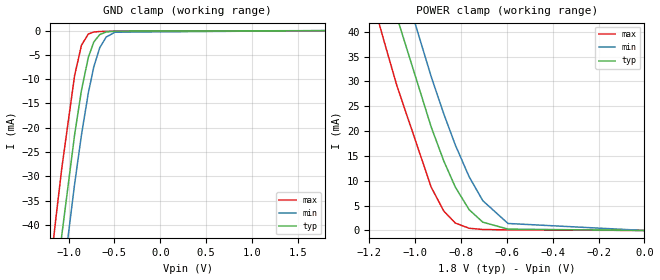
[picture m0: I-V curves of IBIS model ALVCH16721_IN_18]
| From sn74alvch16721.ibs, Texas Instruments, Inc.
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[Model]   ALVCH16721_IN_18
Model_type  Input
Vinl=0.5775
Vinh=1.2675
| variable   typ   min   max
C_comp   1.81pF   1.57pF   1.95pF
[Temperature Range]   40   100   -40
| Ambient temperature   25   85   -40
[Voltage range]   1.8   1.65   1.95
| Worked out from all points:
|   GND clamp passes 1 mA (typ) near -0.67 V on its own axis
|   POWER clamp passes 1 mA (typ) near -0.67 V on its own axis
[GND Clamp]
| ALVCH16721_IN_18
|   Voltage   I(typ)   I(min)   I(max)
-1.8V     -169.8mA   -179.9mA   -157.2mA
-1.22V    -66.13mA   -76.92mA   -52.27mA
-1.14V    -52.74mA   -63.56mA   -38.84mA
-1.075V   -42.24mA   -53mA      -28.43mA
-935mV    -21.5mA    -31.67mA   -9.285mA
-860mV    -12.3mA    -21.51mA   -3.024mA
-785mV    -5.512mA   -12.84mA   -696.8uA
-725mV    -2.333mA   -7.439mA   -282.9uA
-660mV    -799.8uA   -3.501mA   -180.6uA
-590mV    -270.9uA   -1.321mA   -147.3uA
-495mV    -104.2uA   -323.7uA   -120.3uA
1.8V      1.112nA    11.43uA    -24.52uA
[POWER Clamp]
| ALVCH16721_IN_18
|   Voltage   I(typ)   I(min)   I(max)
-1.8V     169.8mA    179.9mA    157.1mA
-1.235V   68.65mA    79.45mA    54.78mA
-1.155V   55.19mA    66.01mA    41.26mA
-1.135V   51.89mA    62.71mA    37.96mA
-1.08V    43mA       53.78mA    29.16mA
-930mV    20.81mA    30.94mA    8.701mA
-875mV    13.96mA    23.43mA    3.896mA
-825mV    8.748mA    17.22mA    1.494mA
-765mV    4.203mA    10.85mA    450.1uA
-705mV    1.671mA    5.993mA    198.8uA
-595mV    272.6uA    1.408mA    118.5uA
-16.28fV  1.112nA    59.61nA    5.224pA
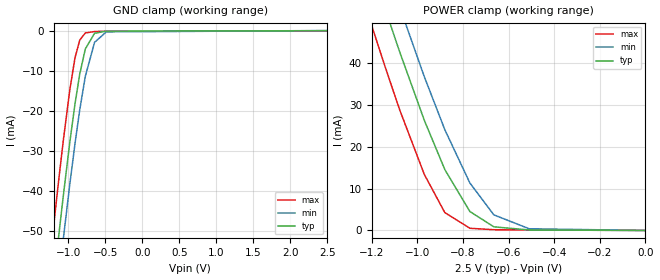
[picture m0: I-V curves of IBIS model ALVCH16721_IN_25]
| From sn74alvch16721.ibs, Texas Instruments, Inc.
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[Model]   ALVCH16721_IN_25
Model_type  Input
Vinl=0.7
Vinh=1.7
| variable   typ   min   max
C_comp   1.84pF   1.53pF   2.06pF
[Temperature Range]   40   100   -40
| Ambient temperature   25   85   -40
[Voltage range]   2.5   2.3   2.7
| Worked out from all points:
|   GND clamp passes 1 mA (typ) near -0.67 V on its own axis
|   POWER clamp passes 1 mA (typ) near -0.67 V on its own axis
[GND Clamp]
| ALVCH16721_IN_25
|   Voltage   I(typ)   I(min)   I(max)
-2.5V     -300.5mA   -309.8mA   -289mA
-1.22V    -66.17mA   -76.96mA   -52.33mA
-1.15V    -54.43mA   -65.24mA   -40.54mA
-1.125V   -50.32mA   -61.12mA   -36.44mA
-1.07V    -41.49mA   -52.23mA   -27.71mA
-980mV    -27.82mA   -38.28mA   -14.75mA
-910mV    -18.27mA   -28.18mA   -6.796mA
-845mV    -10.75mA   -19.66mA   -2.322mA
-770mV    -4.554mA   -11.37mA   -570.4uA
-645mV    -649.1uA   -2.895mA   -203.9uA
-485mV    -117.2uA   -296.6uA   -143.7uA
2.5V      1.114nA    24.46uA    -44.33uA
[POWER Clamp]
| ALVCH16721_IN_25
|   Voltage   I(typ)   I(min)   I(max)
-2.5V     300.4mA    309.8mA    288.9mA
-1.24V    69.54mA    80.33mA    55.69mA
-1.22V    66.13mA    76.94mA    52.26mA
-1.145V   53.57mA    64.39mA    39.65mA
-1.09V    44.63mA    55.42mA    30.77mA
-1.075V   42.25mA    53.01mA    28.42mA
-970mV    26.36mA    36.78mA    13.41mA
-880mV    14.57mA    24.11mA    4.278mA
-770mV    4.531mA    11.35mA    526.6uA
-665mV    874.9uA    3.74mA     180.5uA
-510mV    121uA      408.8uA    122.3uA
-31.15fV  1.114nA    59.61nA    7.128pA
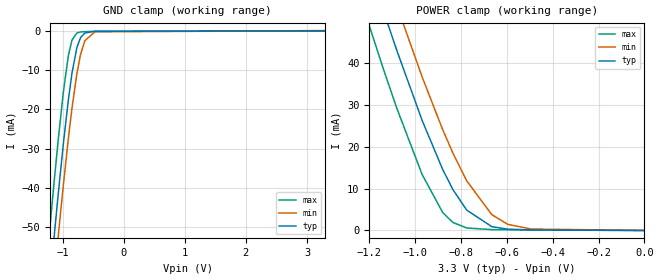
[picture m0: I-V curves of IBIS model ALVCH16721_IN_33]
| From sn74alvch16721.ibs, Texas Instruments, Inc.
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[Model]   ALVCH16721_IN_33
Model_type  Input
Vinl=0.8
Vinh=2.0
| variable   typ   min   max
C_comp   1.84pF   1.50pF   2.09pF
[Temperature Range]   40   100   -40
| Ambient temperature   25   85   -40
[Voltage range]   3.3   3   3.6
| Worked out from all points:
|   GND clamp passes 1 mA (typ) near -0.67 V on its own axis
|   POWER clamp passes 1 mA (typ) near -0.67 V on its own axis
[GND Clamp]
| ALVCH16721_IN_33
|   Voltage   I(typ)   I(min)   I(max)
-3.3V     -452.1mA   -460.8mA   -441.7mA
-1.225V   -67.05mA   -77.83mA   -53.23mA
-1.14V    -52.81mA   -63.61mA   -38.93mA
-1.07V    -41.52mA   -52.25mA   -27.75mA
-985mV    -28.58mA   -39.06mA   -15.45mA
-905mV    -17.66mA   -27.51mA   -6.374mA
-845mV    -10.77mA   -19.68mA   -2.354mA
-765mV    -4.276mA   -10.91mA   -557.3uA
-705mV    -1.739mA   -6.046mA   -298.4uA
-635mV    -574.4uA   -2.545mA   -223.6uA
-470mV    -123.2uA   -255uA     -158.8uA
3.3V      1.116nA    53.49uA    -78.26uA
[POWER Clamp]
| ALVCH16721_IN_33
|   Voltage   I(typ)   I(min)   I(max)
-3.3V     452.1mA    460.8mA    441.5mA
-1.23V    67.86mA    78.66mA    54.01mA
-1.14V    52.78mA    63.6mA     38.86mA
-1.08V    43.07mA    53.84mA    29.23mA
-970mV    26.39mA    36.8mA     13.44mA
-880mV    14.6mA     24.13mA    4.304mA
-835mV    9.751mA    18.46mA    1.894mA
-775mV    4.867mA    11.86mA    599.3uA
-665mV    894uA      3.758mA    201.9uA
-595mV    313uA      1.445mA    165.5uA
-495mV    124uA      344uA      135.2uA
-48.03fV  1.116nA    59.61nA    9.406pA
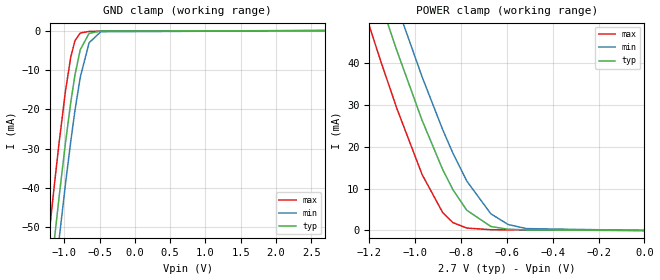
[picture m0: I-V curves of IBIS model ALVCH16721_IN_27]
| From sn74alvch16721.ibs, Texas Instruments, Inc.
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[Model]   ALVCH16721_IN_27
Model_type  Input
Vinl=0.8
Vinh=2.0
| variable   typ   min   max
C_comp   1.85pF   1.55pF   2.04pF
[Temperature Range]   40   100   -40
| Ambient temperature   25   85   -40
[Voltage range]   2.7   2.7   2.7
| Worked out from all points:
|   GND clamp passes 1 mA (typ) near -0.67 V on its own axis
|   POWER clamp passes 1 mA (typ) near -0.67 V on its own axis
[GND Clamp]
| ALVCH16721_IN_27
|   Voltage   I(typ)   I(min)   I(max)
-2.7V     -338.2mA   -347.4mA   -327.1mA
-1.24V    -69.58mA   -80.37mA   -55.76mA
-1.16V    -56.1mA    -66.91mA   -42.2mA
-1.135V   -51.97mA   -62.78mA   -38.07mA
-1.075V   -42.28mA   -53.04mA   -28.48mA
-985mV    -28.56mA   -39.05mA   -15.41mA
-910mV    -18.27mA   -28.19mA   -6.796mA
-850mV    -11.28mA   -20.29mA   -2.551mA
-775mV    -4.875mA   -11.87mA   -619.1uA
-650mV    -708.2uA   -3.102mA   -207.1uA
-485mV    -121.5uA   -303.9uA   -143.7uA
2.7V      1.115nA    59.61nA    7.128pA
[POWER Clamp]
| ALVCH16721_IN_27
|   Voltage   I(typ)   I(min)   I(max)
-2.7V     338.2mA    347.4mA    326.9mA
-1.23V    67.84mA    78.65mA    53.97mA
-1.15V    54.41mA    65.24mA    40.47mA
-1.08V    43.05mA    53.83mA    29.2mA
-970mV    26.37mA    36.79mA    13.41mA
-880mV    14.58mA    24.12mA    4.278mA
-835mV    9.734mA    18.45mA    1.869mA
-775mV    4.852mA    11.85mA    575.1uA
-670mV    956.3uA    3.994mA    184.7uA
-595mV    300.7uA    1.439mA    145.9uA
-515mV    130.2uA    448.2uA    123.5uA
-35.59fV  1.115nA    59.61nA    7.128pA
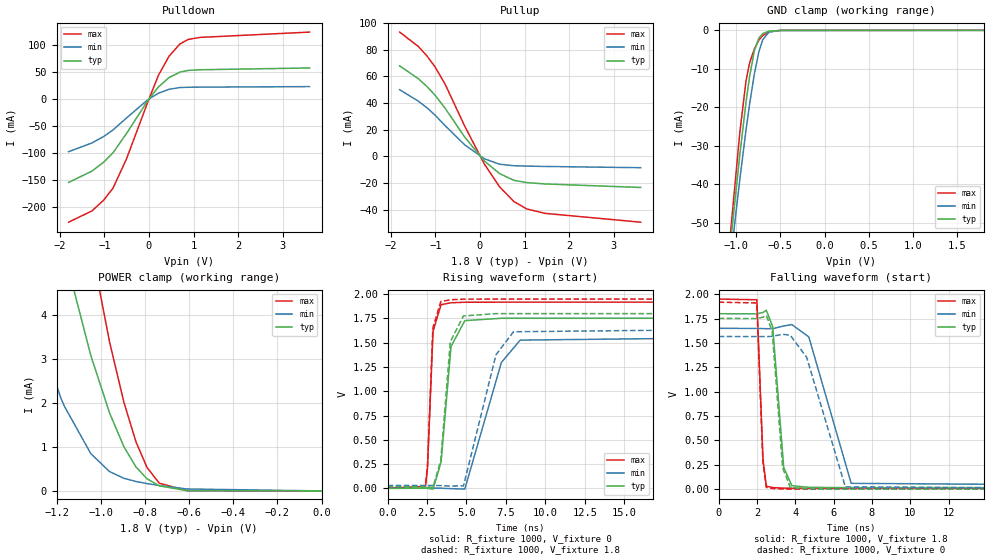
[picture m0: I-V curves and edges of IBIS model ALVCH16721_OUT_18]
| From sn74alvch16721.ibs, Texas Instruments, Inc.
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[Model]   ALVCH16721_OUT_18
Model_type  3-state
Enable   Active-Low
Vref =   0
Rref =   1000
Cref =   30p
Vmeas =   0.9
| variable   typ   min   max
C_comp   7.11pF   6.09pF   8.27pF
| C_pullup   8.07pF   7.48pF   8.71pF
| C_pulldown   9.93pF   7.67pF   11.83pF
| C_tri-state   7.11pF   6.09pF   8.27pF
[Temperature Range]   40   100   -40
| Ambient temperature   25   85   -40
[Voltage range]   1.8   1.65   1.95
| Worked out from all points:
|   slope of the pulldown table from 0 to 0.27 V, typ, clamps not added: 10 ohm
|   slope of the pullup table from 0 to 0.27 V, typ, clamps not added: 30.8 ohm
|   GND clamp passes 1 mA (typ) near -0.71 V on its own axis
|   POWER clamp passes 1 mA (typ) near -0.89 V on its own axis
|   rising waveform, R_fixture 1000, V_fixture 0: 20-80 % time 535ps typ, 1.34ns min, 273ps max; typ from 0 V to 1.75 V
|   falling waveform, R_fixture 1000, V_fixture 1.8: 20-80 % time 386ps typ, 961ps min, 182ps max; typ from 1.8 V to 0.015 V
|   rising waveform, R_fixture 1000, V_fixture 1.8: 20-80 % time 504ps typ, 1.14ns min, 264ps max; typ from 0.015 V to 1.8 V
|   falling waveform, R_fixture 1000, V_fixture 0: 20-80 % time 373ps typ, 973ps min, 182ps max; typ from 1.75 V to 0 V
[GND Clamp]
| ALVCH16721_OUT_18
|   Voltage   I(typ)   I(min)   I(max)
-1.8V     -243.3mA   -228.2mA   -268.4mA
-1.095V   -62.11mA   -65.74mA   -60.44mA
-1.065V   -55.21mA   -59.52mA   -52.47mA
-960mV    -32.27mA   -38.65mA   -26.5mA
-890mV    -18.68mA   -25.89mA   -13.15mA
-850mV    -12.06mA   -19.23mA   -8.522mA
-795mV    -5.259mA   -11.23mA   -4.781mA
-745mV    -2.029mA   -5.614mA   -2.577mA
-700mV    -849.2uA   -2.395mA   -1.322mA
-630mV    -224.4uA   -456.1uA   -398.2uA
-505mV    -19.57uA   -22.32uA   -41.45uA
1.8V      1.196nA    205.5pA    11.39nA
[POWER Clamp]
| ALVCH16721_OUT_18
|   Voltage   I(typ)   I(min)   I(max)
-1.8V     25.11mA    14.18mA    39.93mA
-1.415V   11.83mA    5.639mA    19.65mA
-1.18V    5.742mA    2.103mA    9.959mA
-1.165V   5.414mA    1.93mA     9.427mA
-1.045V   3.081mA    847.9uA    5.599mA
-960mV    1.772mA    439.6uA    3.385mA
-895mV    1.004mA    286.9uA    2.013mA
-840mV    542.1uA    213.7uA    1.108mA
-790mV    274.5uA    166.5uA    530uA
-735mV    115uA      123.6uA    176.7uA
-610mV    7.212uA    44.47uA    5.785uA
-16.28fV  1.196nA    59.55pA    11.28nA
[Pulldown]
| ALVCH16721_OUT_18
|   Voltage   I(typ)   I(min)   I(max)
-1.8V     -154.3mA   -97.53mA   -227.7mA
-1.275V   -133.3mA   -81.3mA    -206.8mA
-1.01V    -116.6mA   -69.29mA   -186.7mA
-805mV    -99.61mA   -57.36mA   -164.8mA
-505mV    -64.22mA   -35.41mA   -111.3mA
-20mV     -2.398mA   -1.172mA   -4.654mA
210mV     21.85mA    10.32mA    43.05mA
450mV     39.36mA    17.78mA    78.77mA
695mV     49.56mA    20.99mA    101.6mA
880mV     52.63mA    21.52mA    109.8mA
1.15V     53.84mA    21.74mA    113.6mA
3.6V      57.13mA    22.68mA    123.4mA
[Pullup]
| ALVCH16721_OUT_18
|   Voltage   I(typ)   I(min)   I(max)
-1.8V     67.82mA    49.93mA    93.11mA
-1.38V    58.14mA    41.32mA    82.29mA
-1.19V    52.37mA    36.44mA    75.34mA
-1.01V    45.98mA    31mA       67.22mA
-780mV    36mA       22.96mA    54.02mA
-340mV    14.33mA    8.546mA    22.47mA
105mV     -3.708mA   -1.929mA   -6.218mA
440mV     -12.97mA   -5.934mA   -22.89mA
760mV     -17.99mA   -7.06mA    -33.91mA
1.05V     -19.72mA   -7.341mA   -39.49mA
1.46V     -20.73mA   -7.61mA    -42.78mA
3.6V      -23.36mA   -8.547mA   -49.39mA
[Ramp]
| ALVCH16721_OUT_18
| variable   typ   min   max
dV/dt_r   1.06/5.42E-10   0.95/1.35E-09   1.16/2.80E-10
dV/dt_f   1.10/4.03E-10   1.00/9.99E-10   1.18/1.87E-10
R_load = 1000
[Rising Waveform]
| ALVCH16721_OUT_18
R_fixture =   1000
C_fixture =   0
L_fixture =   0
V_fixture =   0
V_fixture_min = 0
V_fixture_max = 0
|   Time   V(typ)   V(min)   V(max)
0s        299.4pV    583.6pV    166.6pV
2.405ns   902.4uV    855.7uV    19.84mV
2.53ns    756.5uV    1.082mV    210.1mV
2.88ns    -8.83mV    1.245mV    1.617V
3.39ns    269.6mV    1.194mV    1.892V
4.02ns    1.461V     -3.579mV   1.912V
4.895ns   1.728V     -7.83mV    1.917V
7.21ns    1.752V     1.296V     1.918V
8.4ns     1.752V     1.527V     1.918V
29.99ns   1.752V     1.566V     1.918V
[Falling Waveform]
| ALVCH16721_OUT_18
R_fixture =   1000
C_fixture =   0
L_fixture =   0
V_fixture =   1.8
V_fixture_min = 1.65
V_fixture_max = 1.95
|   Time   V(typ)   V(min)   V(max)
0s        1.8V       1.65V      1.95V
1.995ns   1.798V     1.649V     1.943V
2.315ns   1.812V     1.647V     304.7mV
2.49ns    1.835V     1.646V     30.75mV
2.82ns    1.667V     1.646V     16.49mV
3.395ns   223.6mV    1.674V     10.47mV
3.82ns    36.04mV    1.688V     9.234mV
4.705ns   18.35mV    1.562V     8.527mV
6.915ns   15.22mV    59.74mV    8.376mV
29.99ns   15.11mV    28.63mV    8.373mV
[Rising Waveform]
| ALVCH16721_OUT_18
R_fixture =   1000
C_fixture =   0
L_fixture =   0
V_fixture =   1.8
V_fixture_min = 1.65
V_fixture_max = 1.95
|   Time   V(typ)   V(min)   V(max)
0s        15.11mV    28.63mV    8.373mV
2.4ns     15.31mV    29.18mV    27.06mV
2.53ns    14.99mV    29.2mV     232.7mV
2.87ns    6.365mV    28.66mV    1.651V
3.37ns    286.1mV    27.64mV    1.924V
3.975ns   1.51V      23.18mV    1.943V
4.81ns    1.776V     24.93mV    1.949V
6.87ns    1.8V       1.376V     1.95V
7.98ns    1.8V       1.613V     1.95V
29.99ns   1.8V       1.65V      1.95V
[Falling Waveform]
| ALVCH16721_OUT_18
R_fixture =   1000
C_fixture =   0
L_fixture =   0
V_fixture =   0
V_fixture_min = 0
V_fixture_max = 0
|   Time   V(typ)   V(min)   V(max)
0s        1.752V     1.566V     1.918V
1.99ns    1.75V      1.565V     1.91V
2.31ns    1.764V     1.565V     280.2mV
2.49ns    1.782V     1.565V     16.93mV
2.795ns   1.62V      1.568V     7.697mV
3.34ns    220.6mV    1.589V     2.044mV
3.735ns   19.53mV    1.579V     876.8uV
4.59ns    2.691mV    1.354V     157.9uV
6.61ns    86.48uV    23.6mV     3.955uV
29.99ns   1.05nV     1.235nV    287.2pV
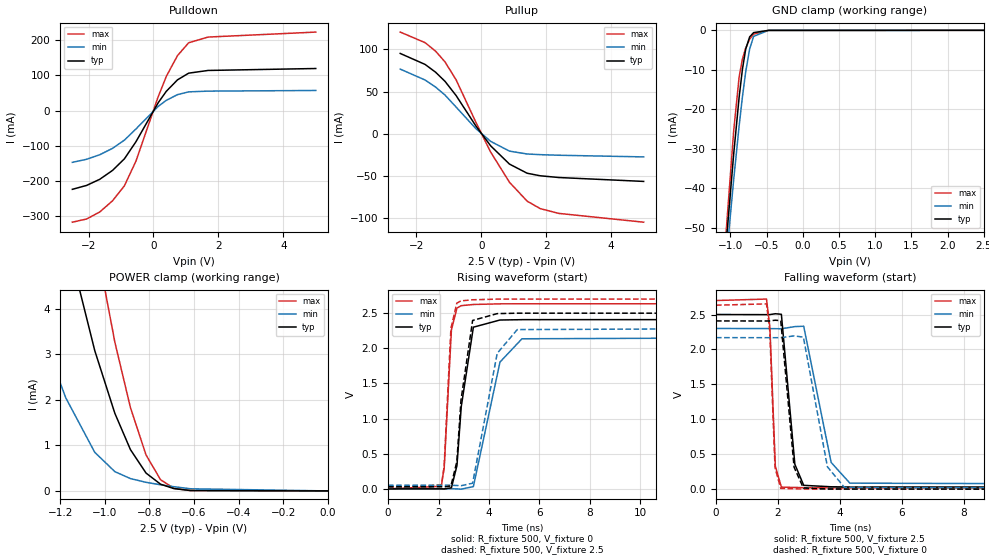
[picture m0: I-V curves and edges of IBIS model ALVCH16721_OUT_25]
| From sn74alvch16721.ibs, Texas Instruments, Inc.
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[Model]   ALVCH16721_OUT_25
Model_type  3-state
Enable   Active-Low
Vref =   0
Rref =   500
Cref =   30p
Vmeas =   1.25
| variable   typ   min   max
C_comp   6.82pF   5.80pF   8.17pF
| C_pullup   7.86pF   7.18pF   8.73pF
| C_pulldown   9.38pF   6.58pF   11.81pF
| C_tri-state   6.82pF   5.80pF   8.17pF
[Temperature Range]   40   100   -40
| Ambient temperature   25   85   -40
[Voltage range]   2.5   2.3   2.7
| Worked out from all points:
|   slope of the pulldown table from 0 to 0.375 V, typ, clamps not added: 7.11 ohm
|   slope of the pullup table from 0 to 0.375 V, typ, clamps not added: 20.7 ohm
|   GND clamp passes 1 mA (typ) near -0.71 V on its own axis
|   POWER clamp passes 1 mA (typ) near -0.89 V on its own axis
|   rising waveform, R_fixture 500, V_fixture 0: 20-80 % time 323ps typ, 588ps min, 209ps max; typ from 0 V to 2.41 V
|   falling waveform, R_fixture 500, V_fixture 2.5: 20-80 % time 228ps typ, 475ps min, 128ps max; typ from 2.5 V to 0.03 V
|   rising waveform, R_fixture 500, V_fixture 2.5: 20-80 % time 308ps typ, 527ps min, 205ps max; typ from 0.03 V to 2.5 V
|   falling waveform, R_fixture 500, V_fixture 0: 20-80 % time 219ps typ, 437ps min, 124ps max; typ from 2.41 V to 0 V
[GND Clamp]
| ALVCH16721_OUT_25
|   Voltage   I(typ)   I(min)   I(max)
-2.5V     -440.5mA   -405.4mA   -490.1mA
-1.09V    -60.95mA   -64.7mA    -59.1mA
-1.07V    -56.36mA   -60.55mA   -53.78mA
-1.055V   -52.94mA   -57.47mA   -49.85mA
-955mV    -31.24mA   -37.7mA    -25.39mA
-880mV    -16.92mA   -24.17mA   -11.77mA
-835mV    -9.895mA   -16.9mA    -7.298mA
-790mV    -4.809mA   -10.58mA   -4.52mA
-735mV    -1.667mA   -4.739mA   -2.241mA
-680mV    -581.8uA   -1.533mA   -953.6uA
-475mV    -10.99uA   -10.29uA   -24.43uA
2.5V      1.037nA    747.3pA    10.72nA
[POWER Clamp]
| ALVCH16721_OUT_25
|   Voltage   I(typ)   I(min)   I(max)
-2.5V     56.58mA    36.27mA    85.37mA
-1.405V   11.53mA    5.461mA    19.19mA
-1.28V    8.118mA    3.43mA     13.78mA
-1.175V   5.632mA    2.045mA    9.78mA
-1.045V   3.081mA    847.9uA    5.599mA
-955mV    1.705mA    423.9uA    3.269mA
-885mV    906.7uA    270.9uA    1.829mA
-815mV    391.2uA    188.7uA    788.2uA
-750mV    147.6uA    134.7uA    246.1uA
-690mV    50.51uA    92.37uA    57.6uA
-615mV    8.308uA    47.11uA    6.732uA
-31.15fV  1.037nA    68.08pA    10.48nA
[Pulldown]
| ALVCH16721_OUT_25
|   Voltage   I(typ)   I(min)   I(max)
-2.5V     -223.2mA   -146.6mA   -316.5mA
-2.06V    -212.1mA   -137.9mA   -307.4mA
-1.655V   -194.7mA   -125mA     -287.5mA
-1.26V    -169.4mA   -106.8mA   -255.7mA
-895mV    -136.5mA   -83.49mA   -213.1mA
-540mV    -88.14mA   -51.89mA   -143.3mA
145mV     22.52mA    12.19mA    39.65mA
395mV     55.03mA    29.41mA    97.31mA
740mV     87.57mA    45.62mA    156.4mA
1.085V    106.6mA    53.52mA    192.9mA
1.685V    114.3mA    55.59mA    209.1mA
5V        119.8mA    57.44mA    223.2mA
[Pullup]
| ALVCH16721_OUT_25
|   Voltage   I(typ)   I(min)   I(max)
-2.5V     95.2mA     76.65mA    120.5mA
-1.735V   82.23mA    63.78mA    108mA
-1.41V    72.97mA    55.35mA    97.9mA
-1.12V    62.15mA    45.9mA     85.18mA
-780mV    45.42mA    31.75mA    64.07mA
-165mV    9.08mA     6.027mA    13.33mA
285mV     -14.15mA   -8.875mA   -21.52mA
865mV     -35.79mA   -20.44mA   -57.31mA
1.41V     -46.63mA   -23.86mA   -79.68mA
1.81V     -49.62mA   -24.62mA   -88.48mA
2.38V     -51.69mA   -25.33mA   -94.16mA
5V        -56.32mA   -27.28mA   -104.6mA
[Ramp]
| ALVCH16721_OUT_25
| variable   typ   min   max
dV/dt_r   1.45/3.37E-10   1.31/5.98E-10   1.58/2.26E-10
dV/dt_f   1.50/2.37E-10   1.38/4.87E-10   1.63/1.39E-10
R_load = 500
[Rising Waveform]
| ALVCH16721_OUT_25
R_fixture =   500
C_fixture =   0
L_fixture =   0
V_fixture =   0
V_fixture_min = 0
V_fixture_max = 0
|   Time   V(typ)   V(min)   V(max)
0s        299.7pV    515.6pV    184.9pV
2.11ns    366.7uV    1.201mV    36.56mV
2.225ns   -1.685mV   1.418mV    304.4mV
2.51ns    15.88mV    1.751mV    2.261V
2.73ns    332.6mV    -54.73uV   2.572V
2.9ns     1.17V      -4.149mV   2.606V
3.38ns    2.3V       32.55mV    2.623V
4.435ns   2.402V     1.804V     2.632V
5.305ns   2.407V     2.135V     2.633V
29.99ns   2.408V     2.169V     2.633V
[Falling Waveform]
| ALVCH16721_OUT_25
R_fixture =   500
C_fixture =   0
L_fixture =   0
V_fixture =   2.5
V_fixture_min = 2.3
V_fixture_max = 2.7
|   Time   V(typ)   V(min)   V(max)
0s        2.5V       2.3V       2.7V
1.63ns    2.498V     2.299V     2.721V
1.74ns    2.499V     2.298V     2.315V
1.915ns   2.511V     2.297V     328.2mV
2.11ns    2.503V     2.296V     29.53mV
2.545ns   355.9mV    2.327V     24.24mV
2.83ns    55mV       2.332V     21.53mV
3.715ns   34.13mV    383.1mV    19.08mV
4.32ns    31.54mV    86.03mV    18.77mV
29.99ns   30.33mV    51.24mV    18.63mV
[Rising Waveform]
| ALVCH16721_OUT_25
R_fixture =   500
C_fixture =   0
L_fixture =   0
V_fixture =   2.5
V_fixture_min = 2.3
V_fixture_max = 2.7
|   Time   V(typ)   V(min)   V(max)
0s        30.33mV    51.24mV    18.63mV
2.11ns    29.78mV    51.74mV    56.73mV
2.22ns    27.83mV    51.63mV    309.7mV
2.49ns    40.82mV    51.02mV    2.282V
2.725ns   387.6mV    48.54mV    2.642V
2.89ns    1.265V     44.74mV    2.674V
3.35ns    2.396V     80.75mV    2.69V
4.325ns   2.493V     1.929V     2.699V
5.12ns    2.499V     2.266V     2.7V
29.99ns   2.5V       2.3V       2.7V
[Falling Waveform]
| ALVCH16721_OUT_25
R_fixture =   500
C_fixture =   0
L_fixture =   0
V_fixture =   0
V_fixture_min = 0
V_fixture_max = 0
|   Time   V(typ)   V(min)   V(max)
0s        2.408V     2.169V     2.633V
1.63ns    2.407V     2.168V     2.652V
1.735ns   2.408V     2.168V     2.267V
1.905ns   2.418V     2.168V     306.6mV
2.09ns    2.413V     2.168V     11.03mV
2.52ns    315.3mV    2.194V     5.093mV
2.82ns    16.48mV    2.176V     2.524mV
3.595ns   3.32mV     320.9mV    478.4uV
4.14ns    1.102mV    27.16mV    160uV
29.99ns   359.2pV    -1.377uV   980.1pV
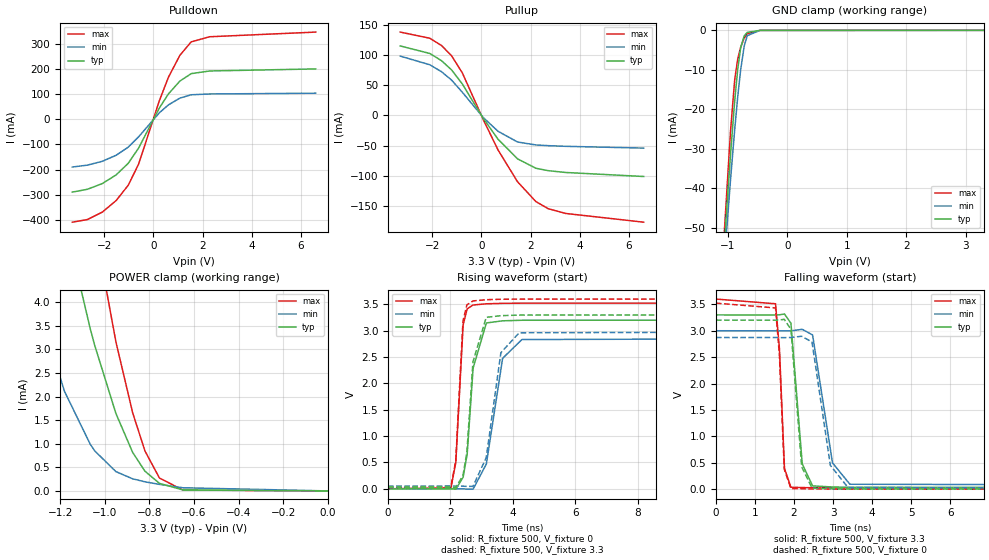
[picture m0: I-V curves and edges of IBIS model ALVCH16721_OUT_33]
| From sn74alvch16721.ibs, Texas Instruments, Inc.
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[Model]   ALVCH16721_OUT_33
Model_type  3-state
Enable   Active-Low
Vref =   0
Rref =   500
Cref =   50p
Vmeas =   1.5
| variable   typ   min   max
C_comp   6.57pF   5.53pF   8.12pF
| C_pullup   7.57pF   6.84pF   8.68pF
| C_pulldown   8.66pF   5.41pF   11.75pF
| C_tri-state   6.57pF   5.53pF   8.12pF
[Temperature Range]   40   100   -40
| Ambient temperature   25   85   -40
[Voltage range]   3.3   3   3.6
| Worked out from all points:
|   slope of the pulldown table from 0 to 0.495 V, typ, clamps not added: 5.84 ohm
|   slope of the pullup table from 0 to 0.495 V, typ, clamps not added: 16.6 ohm
|   GND clamp passes 1 mA (typ) near -0.71 V on its own axis
|   POWER clamp passes 1 mA (typ) near -0.89 V on its own axis
|   rising waveform, R_fixture 500, V_fixture 0: 20-80 % time 246ps typ, 404ps min, 165ps max; typ from 0 V to 3.2 V
|   falling waveform, R_fixture 500, V_fixture 3.3: 20-80 % time 169ps typ, 308ps min, 117ps max; typ from 3.3 V to 0.033 V
|   rising waveform, R_fixture 500, V_fixture 3.3: 20-80 % time 241ps typ, 383ps min, 163ps max; typ from 0.033 V to 3.3 V
|   falling waveform, R_fixture 500, V_fixture 0: 20-80 % time 166ps typ, 287ps min, 118ps max; typ from 3.2 V to 0 V
[GND Clamp]
| ALVCH16721_OUT_33
|   Voltage   I(typ)   I(min)   I(max)
-3.3V     -673.6mA   -616.1mA   -748.3mA
-1.095V   -62.11mA   -65.74mA   -60.44mA
-1.075V   -57.5mA    -61.58mA   -55.11mA
-1.055V   -52.94mA   -57.47mA   -49.85mA
-955mV    -31.24mA   -37.7mA    -25.39mA
-885mV    -17.8mA    -25.02mA   -12.44mA
-835mV    -9.895mA   -16.9mA    -7.298mA
-785mV    -4.39mA    -9.955mA   -4.268mA
-725mV    -1.372mA   -3.954mA   -1.94mA
-675mV    -529.4uA   -1.365mA   -876.7uA
-460mV    -8.239uA   -6.882uA   -18.8uA
3.3V      867.7pA    15.19nA    9.614nA
[POWER Clamp]
| ALVCH16721_OUT_33
|   Voltage   I(typ)   I(min)   I(max)
-3.3V     98.9mA     67.86mA    143.4mA
-1.43V    12.27mA    5.912mA    20.35mA
-1.405V   11.53mA    5.461mA    19.19mA
-1.18V    5.742mA    2.103mA    9.959mA
-1.065V   3.433mA    987.7uA    6.182mA
-1.045V   3.081mA    847.9uA    5.599mA
-950mV    1.639mA    409uA      3.155mA
-875mV    815.2uA    256.4uA    1.654mA
-820mV    418.5uA    193.4uA    847.4uA
-755mV    160.1uA    138.5uA    273.4uA
-650mV    20.91uA    67.05uA    18.91uA
-48.03fV  867.7pA    77.39pA    9.136nA
[Pulldown]
| ALVCH16721_OUT_33
|   Voltage   I(typ)   I(min)   I(max)
-3.3V     -289.4mA   -189.9mA   -408.8mA
-2.685V   -278.1mA   -182.3mA   -398.1mA
-2.08V    -255.5mA   -167.1mA   -368.8mA
-1.52V    -221.2mA   -143.2mA   -323.1mA
-1.03V    -175.5mA   -111.2mA   -262.7mA
-605mV    -114.8mA   -70.11mA   -178.6mA
240mV     44.44mA    25.45mA    73.3mA
610mV     100.6mA    56.89mA    166.8mA
1.075V    151.3mA    83.7mA     253.6mA
1.535V    180.8mA    96.88mA    306.9mA
2.285V    191.4mA    100.1mA    327.2mA
6.6V      199.5mA    103.1mA    345.7mA
[Pullup]
| ALVCH16721_OUT_33
|   Voltage   I(typ)   I(min)   I(max)
-3.3V     115.4mA    98.49mA    138.4mA
-2.1V     102.9mA    84.17mA    128.2mA
-1.625V   91.01mA    72.67mA    116.2mA
-1.215V   75.74mA    58.82mA    99.26mA
-775mV    52.22mA    38.43mA    70.63mA
80mV      -5.193mA   -3.635mA   -7.301mA
680mV     -39.7mA    -26.5mA    -57.58mA
1.47V     -72.16mA   -44.16mA   -110.2mA
2.215V    -87.78mA   -49.09mA   -143.1mA
2.72V     -91.81mA   -50.28mA   -155mA
3.43V     -94.82mA   -51.36mA   -162.9mA
6.6V      -101.5mA   -54.33mA   -177.4mA
[Ramp]
| ALVCH16721_OUT_33
| variable   typ   min   max
dV/dt_r   1.92/2.51E-10   1.73/4.16E-10   2.12/1.73E-10
dV/dt_f   1.98/1.75E-10   1.80/3.18E-10   2.15/1.24E-10
R_load = 500
[Rising Waveform]
| ALVCH16721_OUT_33
R_fixture =   500
C_fixture =   0
L_fixture =   0
V_fixture =   0
V_fixture_min = 0
V_fixture_max = 0
|   Time   V(typ)   V(min)   V(max)
0s        328.6pV    525.9pV    218.6pV
2.015ns   -595uV     1.751mV    20.08mV
2.17ns    -5.72mV    1.903mV    497.8mV
2.405ns   219mV      -1.234mV   3.108V
2.535ns   659.9mV    -5.674mV   3.414V
2.725ns   2.29V      -6.736mV   3.487V
3.15ns    3.147V     472.8mV    3.51V
3.67ns    3.187V     2.476V     3.519V
4.29ns    3.198V     2.832V     3.522V
28ns      3.201V     2.872V     3.523V
[Falling Waveform]
| ALVCH16721_OUT_33
R_fixture =   500
C_fixture =   0
L_fixture =   0
V_fixture =   3.3
V_fixture_min = 3
V_fixture_max = 3.6
|   Time   V(typ)   V(min)   V(max)
0s        3.3V       3V         3.6V
1.525ns   3.299V     2.999V     3.511V
1.625ns   3.302V     2.998V     2.669V
1.755ns   3.317V     2.997V     390.7mV
1.92ns    3.142V     2.998V     35.87mV
2.21ns    476.8mV    3.027V     30.51mV
2.475ns   62.17mV    2.92V      26.44mV
2.985ns   41.26mV    498mV      23.42mV
3.43ns    36.22mV    93.34mV    22.55mV
28ns      33.17mV    52.29mV    22mV
[Rising Waveform]
| ALVCH16721_OUT_33
R_fixture =   500
C_fixture =   0
L_fixture =   0
V_fixture =   3.3
V_fixture_min = 3
V_fixture_max = 3.6
|   Time   V(typ)   V(min)   V(max)
0s        33.17mV    52.29mV    22mV
2.015ns   32.02mV    53.34mV    42.65mV
2.17ns    27.23mV    53.03mV    539.4mV
2.4ns     250.7mV    49.54mV    3.179V
2.525ns   691mV      45.61mV    3.49V
2.72ns    2.408V     45.28mV    3.564V
3.145ns   3.253V     591.8mV    3.588V
3.615ns   3.285V     2.583V     3.596V
4.2ns     3.296V     2.96V      3.599V
28ns      3.3V       3V         3.6V
[Falling Waveform]
| ALVCH16721_OUT_33
R_fixture =   500
C_fixture =   0
L_fixture =   0
V_fixture =   0
V_fixture_min = 0
V_fixture_max = 0
|   Time   V(typ)   V(min)   V(max)
0s        3.201V     2.872V     3.523V
1.525ns   3.201V     2.871V     3.432V
1.625ns   3.204V     2.871V     2.538V
1.75ns    3.216V     2.87V      376.8mV
1.92ns    3.027V     2.872V     11.96mV
2.195ns   425.1mV    2.896V     7.992mV
2.46ns    21.13mV    2.786V     4.193mV
2.93ns    7.233mV    450.8mV    1.454mV
3.385ns   2.583mV    28.69mV    552.4uV
28ns      801.4pV    71.71nV    1.279nV
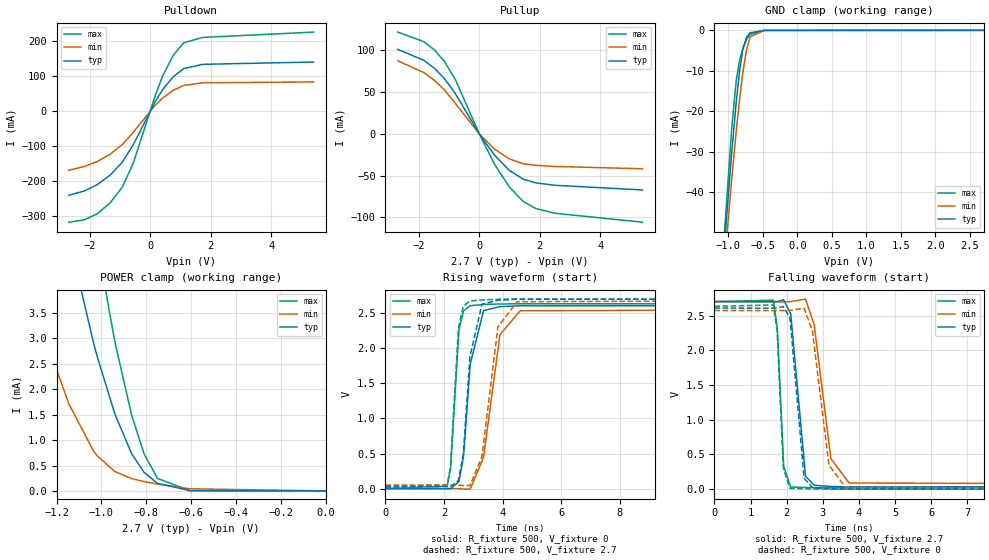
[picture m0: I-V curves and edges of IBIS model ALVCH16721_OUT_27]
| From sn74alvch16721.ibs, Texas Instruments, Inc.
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[Model]   ALVCH16721_OUT_27
Model_type  3-state
Enable   Active-Low
Vref =   0
Rref =   500
Cref =   50p
Vmeas =   1.5
| variable   typ   min   max
C_comp   6.75pF   5.79pF   8.13pF
| C_pullup   7.81pF   7.10pF   8.70pF
| C_pulldown   9.26pF   6.51pF   11.78pF
| C_tri-state   6.75pF   5.79pF   8.13pF
[Temperature Range]   40   100   -40
| Ambient temperature   25   85   -40
[Voltage range]   2.7   2.7   2.7
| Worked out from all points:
|   slope of the pulldown table from 0 to 0.405 V, typ, clamps not added: 6.69 ohm
|   slope of the pullup table from 0 to 0.405 V, typ, clamps not added: 19.3 ohm
|   GND clamp passes 1 mA (typ) near -0.71 V on its own axis
|   POWER clamp passes 1 mA (typ) near -0.89 V on its own axis
|   rising waveform, R_fixture 500, V_fixture 0: 20-80 % time 300ps typ, 456ps min, 209ps max; typ from 0 V to 2.61 V
|   falling waveform, R_fixture 500, V_fixture 2.7: 20-80 % time 211ps typ, 355ps min, 128ps max; typ from 2.7 V to 0.031 V
|   rising waveform, R_fixture 500, V_fixture 2.7: 20-80 % time 289ps typ, 428ps min, 205ps max; typ from 0.031 V to 2.7 V
|   falling waveform, R_fixture 500, V_fixture 0: 20-80 % time 204ps typ, 332ps min, 124ps max; typ from 2.61 V to 0 V
[GND Clamp]
| ALVCH16721_OUT_27
|   Voltage   I(typ)   I(min)   I(max)
-2.7V     -498.3mA   -457.5mA   -554.5mA
-1.09V    -60.95mA   -64.7mA    -59.1mA
-1.07V    -56.36mA   -60.55mA   -53.78mA
-1.05V    -51.81mA   -56.45mA   -48.55mA
-950mV    -30.21mA   -36.76mA   -24.29mA
-885mV    -17.8mA    -25.02mA   -12.44mA
-835mV    -9.895mA   -16.9mA    -7.298mA
-790mV    -4.809mA   -10.58mA   -4.52mA
-735mV    -1.667mA   -4.739mA   -2.241mA
-680mV    -581.8uA   -1.533mA   -953.6uA
-475mV    -10.99uA   -10.29uA   -24.43uA
2.7V      993.5pA    73.38pA    10.48nA
[POWER Clamp]
| ALVCH16721_OUT_27
|   Voltage   I(typ)   I(min)   I(max)
-2.7V     66.72mA    43.69mA    99.53mA
-1.38V    10.81mA    5.024mA    18.06mA
-1.25V    7.371mA    3.002mA    12.59mA
-1.145V   4.99mA     1.712mA    8.736mA
-1.035V   2.911mA    784.5uA    5.316mA
-1.02V    2.664mA    697.4uA    4.902mA
-940mV    1.512mA    381.4uA    2.931mA
-865mV    729.7uA    243uA      1.487mA
-810mV    365.2uA    184.1uA    731.5uA
-750mV    147.6uA    134.7uA    246.1uA
-605mV    6.248uA    41.88uA    4.965uA
-35.59fV  993.5pA    73.38pA    10.48nA
[Pulldown]
| ALVCH16721_OUT_27
|   Voltage   I(typ)   I(min)   I(max)
-2.7V     -241mA     -169.5mA   -317.8mA
-2.19V    -228.9mA   -159mA     -311.3mA
-1.76V    -210.7mA   -144.7mA   -293.9mA
-1.33V    -183.4mA   -123.7mA   -262.3mA
-930mV    -146.9mA   -96.36mA   -218mA
-565mV    -96.6mA    -61.23mA   -149.3mA
150mV     24.79mA    14.91mA    40.94mA
405mV     60.55mA    36.48mA    99.34mA
755mV     97.31mA    58.66mA    158.4mA
1.105V    120.6mA    72.64mA    194.3mA
1.735V    132.7mA    79.91mA    209.5mA
5.4V      139.3mA    82.52mA    224.7mA
[Pullup]
| ALVCH16721_OUT_27
|   Voltage   I(typ)   I(min)   I(max)
-2.7V     101.3mA    87.69mA    122mA
-1.84V    88.28mA    73.59mA    110.6mA
-1.485V   78.58mA    64.13mA    100.6mA
-1.165V   66.78mA    53.2mA     87.42mA
-795mV    48.39mA    36.71mA    65.2mA
5mV       -285.2uA   -208.7uA   -398.2uA
500mV     -25.34mA   -18.03mA   -36.1mA
990mV     -43.56mA   -29.92mA   -63.47mA
1.455V    -54.23mA   -35.75mA   -80.99mA
1.87V     -58.62mA   -37.61mA   -89.33mA
2.495V    -61.46mA   -38.9mA    -94.92mA
5.4V      -67.09mA   -41.72mA   -105.7mA
[Ramp]
| ALVCH16721_OUT_27
| variable   typ   min   max
dV/dt_r   1.57/3.15E-10   1.55/4.65E-10   1.58/2.26E-10
dV/dt_f   1.62/2.21E-10   1.62/3.68E-10   1.63/1.39E-10
R_load = 500
[Rising Waveform]
| ALVCH16721_OUT_27
R_fixture =   500
C_fixture =   0
L_fixture =   0
V_fixture =   0
V_fixture_min = 0
V_fixture_max = 0
|   Time   V(typ)   V(min)   V(max)
0s        305.4pV    517pV      184.9pV
2.11ns    -567.5uV   1.643mV    36.56mV
2.225ns   -3.734mV   1.819mV    304.4mV
2.51ns    102mV      -700.1uV   2.261V
2.665ns   451.6mV    -5.66mV    2.532V
2.895ns   1.771V     -7.784mV   2.606V
3.35ns    2.536V     444.5mV    2.623V
3.91ns    2.592V     2.192V     2.63V
4.6ns     2.604V     2.533V     2.633V
28ns      2.607V     2.572V     2.633V
[Falling Waveform]
| ALVCH16721_OUT_27
R_fixture =   500
C_fixture =   0
L_fixture =   0
V_fixture =   2.7
V_fixture_min = 2.7
V_fixture_max = 2.7
|   Time   V(typ)   V(min)   V(max)
0s        2.7V       2.7V       2.7V
1.63ns    2.698V     2.698V     2.721V
1.74ns    2.701V     2.697V     2.315V
1.915ns   2.726V     2.696V     328.2mV
2.11ns    2.525V     2.7V       29.53mV
2.52ns    185mV      2.737V     24.62mV
2.76ns    56.51mV    2.367V     22.03mV
3.22ns    39.16mV    441.8mV    19.87mV
3.725ns   33.74mV    89.14mV    19.07mV
28ns      30.87mV    51.38mV    18.63mV
[Rising Waveform]
| ALVCH16721_OUT_27
R_fixture =   500
C_fixture =   0
L_fixture =   0
V_fixture =   2.7
V_fixture_min = 2.7
V_fixture_max = 2.7
|   Time   V(typ)   V(min)   V(max)
0s        30.87mV    51.38mV    18.63mV
2.11ns    29.48mV    52.11mV    56.73mV
2.22ns    26.65mV    51.94mV    309.7mV
2.49ns    114mV      49.08mV    2.282V
2.655ns   482mV      44.25mV    2.598V
2.885ns   1.879V     42.83mV    2.673V
3.295ns   2.625V     453.1mV    2.688V
3.84ns    2.684V     2.303V     2.697V
4.495ns   2.696V     2.662V     2.699V
28ns      2.7V       2.7V       2.7V
[Falling Waveform]
| ALVCH16721_OUT_27
R_fixture =   500
C_fixture =   0
L_fixture =   0
V_fixture =   0
V_fixture_min = 0
V_fixture_max = 0
|   Time   V(typ)   V(min)   V(max)
0s        2.607V     2.572V     2.633V
1.63ns    2.606V     2.571V     2.652V
1.735ns   2.609V     2.571V     2.267V
1.905ns   2.629V     2.571V     306.6mV
2.09ns    2.464V     2.575V     11.03mV
2.48ns    158.6mV    2.605V     5.662mV
2.71ns    22.89mV    2.28V      3.237mV
3.165ns   6.764mV    349.6mV    1.18mV
3.62ns    2.498mV    29.18mV    454.5uV
28ns      547.3pV    -16.59nV   978.4pV
